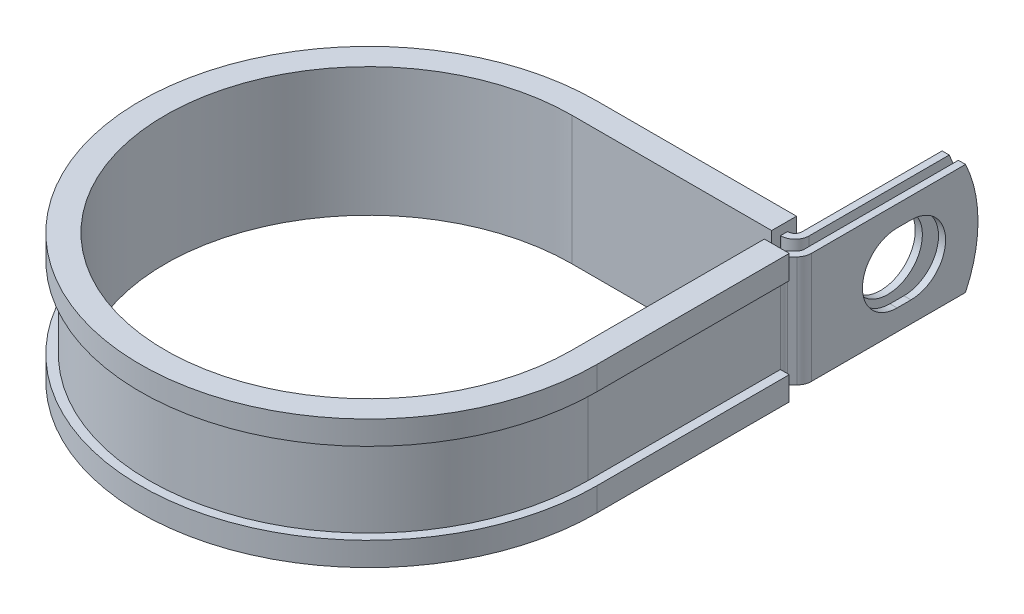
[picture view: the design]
ISO-10303-21;
HEADER;
FILE_DESCRIPTION(('STEP AP214'),'2;1');
FILE_NAME('part.step','',(''),(''),'','','');
FILE_SCHEMA(('AUTOMOTIVE_DESIGN { 1 0 10303 214 1 1 1 1 }'));
ENDSEC;
DATA;
#1=APPLICATION_CONTEXT('core data for automotive mechanical design processes');
#2=APPLICATION_PROTOCOL_DEFINITION('international standard','automotive_design',2000,#1);
#3=PRODUCT_CONTEXT('',#1,'mechanical');
#4=PRODUCT('Part','Part','',(#3));
#5=PRODUCT_RELATED_PRODUCT_CATEGORY('part','',(#4));
#6=PRODUCT_DEFINITION_FORMATION('','',#4);
#7=PRODUCT_DEFINITION_CONTEXT('part definition',#1,'design');
#8=PRODUCT_DEFINITION('design','',#6,#7);
#9=PRODUCT_DEFINITION_SHAPE('','',#8);
#10=(LENGTH_UNIT() NAMED_UNIT(*) SI_UNIT(.MILLI.,.METRE.));
#11=(NAMED_UNIT(*) PLANE_ANGLE_UNIT() SI_UNIT($,.RADIAN.));
#12=(NAMED_UNIT(*) SI_UNIT($,.STERADIAN.) SOLID_ANGLE_UNIT());
#13=UNCERTAINTY_MEASURE_WITH_UNIT(LENGTH_MEASURE(1.E-05),#10,'distance_accuracy_value','');
#14=(GEOMETRIC_REPRESENTATION_CONTEXT(3) GLOBAL_UNCERTAINTY_ASSIGNED_CONTEXT((#13)) GLOBAL_UNIT_ASSIGNED_CONTEXT((#10,
#11,#12)) REPRESENTATION_CONTEXT('',''));
#15=CARTESIAN_POINT('',(0.,0.,0.));
#16=DIRECTION('',(0.,0.,1.));
#17=DIRECTION('',(1.,0.,0.));
#18=AXIS2_PLACEMENT_3D('',#15,#16,#17);
#19=CARTESIAN_POINT('',(37.1272698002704,-9.525,-36.449));
#20=DIRECTION('',(0.,1.,0.));
#21=DIRECTION('',(1.,0.,0.));
#22=AXIS2_PLACEMENT_3D('',#19,#20,#21);
#23=PLANE('',#22);
#24=DIRECTION('',(0.,0.,-1.));
#25=VECTOR('',#24,1.);
#26=CARTESIAN_POINT('',(34.2824698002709,-9.525,-36.449));
#27=LINE('',#26,#25);
#28=CARTESIAN_POINT('',(34.2824698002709,-9.525,-36.449));
#29=VERTEX_POINT('',#28);
#30=CARTESIAN_POINT('',(34.282469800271,-9.525,-37.6682));
#31=VERTEX_POINT('',#30);
#32=EDGE_CURVE('E505',#29,#31,#27,.T.);
#33=ORIENTED_EDGE('',*,*,#32,.T.);
#34=DIRECTION('',(1.,0.,0.));
#35=VECTOR('',#34,1.);
#36=CARTESIAN_POINT('',(0.,-9.525,-37.6682));
#37=LINE('',#36,#35);
#38=CARTESIAN_POINT('',(34.3332698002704,-9.525,-37.6682));
#39=VERTEX_POINT('',#38);
#40=EDGE_CURVE('E392',#39,#31,#37,.F.);
#41=ORIENTED_EDGE('',*,*,#40,.F.);
#42=CARTESIAN_POINT('',(34.3332698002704,-9.525,-38.8874));
#43=DIRECTION('',(0.,1.,0.));
#44=DIRECTION('',(1.,0.,0.));
#45=AXIS2_PLACEMENT_3D('',#42,#43,#44);
#46=CIRCLE('',#45,1.2192);
#47=CARTESIAN_POINT('',(35.5524698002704,-9.525,-38.8874));
#48=VERTEX_POINT('',#47);
#49=EDGE_CURVE('E390',#48,#39,#46,.F.);
#50=ORIENTED_EDGE('',*,*,#49,.F.);
#51=DIRECTION('',(0.,0.,1.));
#52=VECTOR('',#51,1.);
#53=CARTESIAN_POINT('',(35.5524698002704,-9.525,-65.0748));
#54=LINE('',#53,#52);
#55=CARTESIAN_POINT('',(35.5524698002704,-9.525,-62.9302631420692));
#56=VERTEX_POINT('',#55);
#57=EDGE_CURVE('E388',#56,#48,#54,.T.);
#58=ORIENTED_EDGE('',*,*,#57,.F.);
#59=DIRECTION('',(-1.,0.,0.));
#60=VECTOR('',#59,1.);
#61=CARTESIAN_POINT('',(39.5656698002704,-9.525,-62.9302631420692));
#62=LINE('',#61,#60);
#63=CARTESIAN_POINT('',(36.7716698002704,-9.525,-62.9302631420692));
#64=VERTEX_POINT('',#63);
#65=EDGE_CURVE('E11',#64,#56,#62,.T.);
#66=ORIENTED_EDGE('',*,*,#65,.F.);
#67=DIRECTION('',(0.,0.,1.));
#68=VECTOR('',#67,1.);
#69=CARTESIAN_POINT('',(36.7716698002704,-9.525,-65.0748));
#70=LINE('',#69,#68);
#71=CARTESIAN_POINT('',(36.7716698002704,-9.525,-38.8874));
#72=VERTEX_POINT('',#71);
#73=EDGE_CURVE('E386',#64,#72,#70,.T.);
#74=ORIENTED_EDGE('',*,*,#73,.T.);
#75=CARTESIAN_POINT('',(34.3332698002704,-9.525,-38.8874));
#76=DIRECTION('',(0.,-1.,0.));
#77=DIRECTION('',(0.,0.,1.));
#78=AXIS2_PLACEMENT_3D('',#75,#76,#77);
#79=CIRCLE('',#78,2.4384);
#80=CARTESIAN_POINT('',(34.3332698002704,-9.525,-36.449));
#81=VERTEX_POINT('',#80);
#82=EDGE_CURVE('E383',#72,#81,#79,.T.);
#83=ORIENTED_EDGE('',*,*,#82,.T.);
#84=DIRECTION('',(-1.,0.,0.));
#85=VECTOR('',#84,1.);
#86=CARTESIAN_POINT('',(0.,-9.525,-36.449));
#87=LINE('',#86,#85);
#88=EDGE_CURVE('E380',#81,#29,#87,.T.);
#89=ORIENTED_EDGE('',*,*,#88,.T.);
#90=EDGE_LOOP('',(#33,#41,#50,#58,#66,#74,#83,#89));
#91=FACE_BOUND('',#90,.T.);
#92=ADVANCED_FACE('F36',(#91),#23,.F.);
#93=CARTESIAN_POINT('',(37.1272698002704,9.525,-36.449));
#94=DIRECTION('',(0.,1.,0.));
#95=DIRECTION('',(1.,0.,0.));
#96=AXIS2_PLACEMENT_3D('',#93,#94,#95);
#97=PLANE('',#96);
#98=DIRECTION('',(1.,0.,0.));
#99=VECTOR('',#98,1.);
#100=CARTESIAN_POINT('',(0.,9.525,-37.6682));
#101=LINE('',#100,#99);
#102=CARTESIAN_POINT('',(34.3332698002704,9.525,-37.6682));
#103=VERTEX_POINT('',#102);
#104=CARTESIAN_POINT('',(34.282469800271,9.525,-37.6682));
#105=VERTEX_POINT('',#104);
#106=EDGE_CURVE('E350',#103,#105,#101,.F.);
#107=ORIENTED_EDGE('',*,*,#106,.T.);
#108=DIRECTION('',(0.,0.,1.));
#109=VECTOR('',#108,1.);
#110=CARTESIAN_POINT('',(34.282469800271,9.525,-37.6682));
#111=LINE('',#110,#109);
#112=CARTESIAN_POINT('',(34.2824698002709,9.525,-36.449));
#113=VERTEX_POINT('',#112);
#114=EDGE_CURVE('E499',#105,#113,#111,.T.);
#115=ORIENTED_EDGE('',*,*,#114,.T.);
#116=DIRECTION('',(-1.,0.,0.));
#117=VECTOR('',#116,1.);
#118=CARTESIAN_POINT('',(0.,9.525,-36.449));
#119=LINE('',#118,#117);
#120=CARTESIAN_POINT('',(34.3332698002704,9.525,-36.449));
#121=VERTEX_POINT('',#120);
#122=EDGE_CURVE('E607',#121,#113,#119,.T.);
#123=ORIENTED_EDGE('',*,*,#122,.F.);
#124=CARTESIAN_POINT('',(34.3332698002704,9.525,-38.8874));
#125=DIRECTION('',(0.,-1.,0.));
#126=DIRECTION('',(0.,0.,1.));
#127=AXIS2_PLACEMENT_3D('',#124,#125,#126);
#128=CIRCLE('',#127,2.4384);
#129=CARTESIAN_POINT('',(36.7716698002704,9.525,-38.8874));
#130=VERTEX_POINT('',#129);
#131=EDGE_CURVE('E352',#130,#121,#128,.T.);
#132=ORIENTED_EDGE('',*,*,#131,.F.);
#133=DIRECTION('',(0.,0.,1.));
#134=VECTOR('',#133,1.);
#135=CARTESIAN_POINT('',(36.7716698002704,9.525,-65.0748));
#136=LINE('',#135,#134);
#137=CARTESIAN_POINT('',(36.7716698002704,9.525,-62.9302631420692));
#138=VERTEX_POINT('',#137);
#139=EDGE_CURVE('E343',#138,#130,#136,.T.);
#140=ORIENTED_EDGE('',*,*,#139,.F.);
#141=DIRECTION('',(-1.,0.,0.));
#142=VECTOR('',#141,1.);
#143=CARTESIAN_POINT('',(39.5656698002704,9.525,-62.9302631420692));
#144=LINE('',#143,#142);
#145=CARTESIAN_POINT('',(35.5524698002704,9.525,-62.9302631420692));
#146=VERTEX_POINT('',#145);
#147=EDGE_CURVE('E44',#138,#146,#144,.T.);
#148=ORIENTED_EDGE('',*,*,#147,.T.);
#149=DIRECTION('',(0.,0.,1.));
#150=VECTOR('',#149,1.);
#151=CARTESIAN_POINT('',(35.5524698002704,9.525,-65.0748));
#152=LINE('',#151,#150);
#153=CARTESIAN_POINT('',(35.5524698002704,9.525,-38.8874));
#154=VERTEX_POINT('',#153);
#155=EDGE_CURVE('E340',#146,#154,#152,.T.);
#156=ORIENTED_EDGE('',*,*,#155,.T.);
#157=CARTESIAN_POINT('',(34.3332698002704,9.525,-38.8874));
#158=DIRECTION('',(0.,1.,0.));
#159=DIRECTION('',(1.,0.,0.));
#160=AXIS2_PLACEMENT_3D('',#157,#158,#159);
#161=CIRCLE('',#160,1.2192);
#162=EDGE_CURVE('E348',#154,#103,#161,.F.);
#163=ORIENTED_EDGE('',*,*,#162,.T.);
#164=EDGE_LOOP('',(#107,#115,#123,#132,#140,#148,#156,#163));
#165=FACE_BOUND('',#164,.T.);
#166=ADVANCED_FACE('F339',(#165),#97,.T.);
#167=CARTESIAN_POINT('',(0.,9.525,-36.449));
#168=DIRECTION('',(0.,0.,1.));
#169=DIRECTION('',(1.,0.,0.));
#170=AXIS2_PLACEMENT_3D('',#167,#168,#169);
#171=PLANE('',#170);
#172=ORIENTED_EDGE('',*,*,#122,.T.);
#173=DIRECTION('',(0.,-1.,0.));
#174=VECTOR('',#173,1.);
#175=CARTESIAN_POINT('',(34.2824698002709,9.525,-36.449));
#176=LINE('',#175,#174);
#177=EDGE_CURVE('E502',#113,#29,#176,.T.);
#178=ORIENTED_EDGE('',*,*,#177,.T.);
#179=ORIENTED_EDGE('',*,*,#88,.F.);
#180=DIRECTION('',(0.,-1.,0.));
#181=VECTOR('',#180,1.);
#182=CARTESIAN_POINT('',(34.3332698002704,9.525,-36.449));
#183=LINE('',#182,#181);
#184=EDGE_CURVE('E326',#121,#81,#183,.T.);
#185=ORIENTED_EDGE('',*,*,#184,.F.);
#186=EDGE_LOOP('',(#172,#178,#179,#185));
#187=FACE_BOUND('',#186,.T.);
#188=ADVANCED_FACE('F617',(#187),#171,.T.);
#189=CARTESIAN_POINT('',(39.5656698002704,9.525,-36.449));
#190=DIRECTION('',(-1.,0.,0.));
#191=DIRECTION('',(0.,0.,1.));
#192=AXIS2_PLACEMENT_3D('',#189,#190,#191);
#193=PLANE('',#192);
#194=CARTESIAN_POINT('',(39.5656698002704,0.,-53.5685999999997));
#195=DIRECTION('',(1.,0.,0.));
#196=DIRECTION('',(0.,0.,-1.));
#197=AXIS2_PLACEMENT_3D('',#194,#195,#196);
#198=CIRCLE('',#197,5.9436);
#199=CARTESIAN_POINT('',(39.5656698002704,-5.9436,-53.5686000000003));
#200=VERTEX_POINT('',#199);
#201=CARTESIAN_POINT('',(39.5656698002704,5.9436,-53.5686000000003));
#202=VERTEX_POINT('',#201);
#203=EDGE_CURVE('E562',#200,#202,#198,.T.);
#204=ORIENTED_EDGE('',*,*,#203,.F.);
#205=DIRECTION('',(0.,0.,-1.));
#206=VECTOR('',#205,1.);
#207=CARTESIAN_POINT('',(39.5656698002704,-5.9436,-51.1809999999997));
#208=LINE('',#207,#206);
#209=CARTESIAN_POINT('',(39.5656698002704,-5.9436,-51.1809999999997));
#210=VERTEX_POINT('',#209);
#211=EDGE_CURVE('E565',#210,#200,#208,.T.);
#212=ORIENTED_EDGE('',*,*,#211,.F.);
#213=CARTESIAN_POINT('',(39.5656698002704,0.,-51.1809999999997));
#214=DIRECTION('',(1.,0.,0.));
#215=DIRECTION('',(0.,0.,-1.));
#216=AXIS2_PLACEMENT_3D('',#213,#214,#215);
#217=CIRCLE('',#216,5.9436);
#218=CARTESIAN_POINT('',(39.5656698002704,5.9436,-51.1809999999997));
#219=VERTEX_POINT('',#218);
#220=EDGE_CURVE('E558',#219,#210,#217,.T.);
#221=ORIENTED_EDGE('',*,*,#220,.F.);
#222=DIRECTION('',(0.,0.,1.));
#223=VECTOR('',#222,1.);
#224=CARTESIAN_POINT('',(39.5656698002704,5.9436,-51.1809999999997));
#225=LINE('',#224,#223);
#226=EDGE_CURVE('E559',#202,#219,#225,.T.);
#227=ORIENTED_EDGE('',*,*,#226,.F.);
#228=EDGE_LOOP('',(#204,#212,#221,#227));
#229=FACE_BOUND('',#228,.T.);
#230=DIRECTION('',(0.,0.,-1.));
#231=VECTOR('',#230,1.);
#232=CARTESIAN_POINT('',(39.5656698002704,-9.525,-36.449));
#233=LINE('',#232,#231);
#234=CARTESIAN_POINT('',(39.5656698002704,-9.525,-36.449));
#235=VERTEX_POINT('',#234);
#236=CARTESIAN_POINT('',(39.5656698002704,-9.525,-62.9302631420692));
#237=VERTEX_POINT('',#236);
#238=EDGE_CURVE('E364',#235,#237,#233,.T.);
#239=ORIENTED_EDGE('',*,*,#238,.T.);
#240=CARTESIAN_POINT('',(39.5656698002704,0.,-42.8498));
#241=DIRECTION('',(-1.,0.,0.));
#242=DIRECTION('',(0.,0.,1.));
#243=AXIS2_PLACEMENT_3D('',#240,#241,#242);
#244=CIRCLE('',#243,22.225);
#245=CARTESIAN_POINT('',(39.5656698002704,9.525,-62.9302631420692));
#246=VERTEX_POINT('',#245);
#247=EDGE_CURVE('E550',#246,#237,#244,.T.);
#248=ORIENTED_EDGE('',*,*,#247,.F.);
#249=DIRECTION('',(0.,0.,-1.));
#250=VECTOR('',#249,1.);
#251=CARTESIAN_POINT('',(39.5656698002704,9.525,-36.449));
#252=LINE('',#251,#250);
#253=CARTESIAN_POINT('',(39.5656698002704,9.525,-36.449));
#254=VERTEX_POINT('',#253);
#255=EDGE_CURVE('E401',#254,#246,#252,.T.);
#256=ORIENTED_EDGE('',*,*,#255,.F.);
#257=DIRECTION('',(0.,-1.,0.));
#258=VECTOR('',#257,1.);
#259=CARTESIAN_POINT('',(39.5656698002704,9.525,-36.449));
#260=LINE('',#259,#258);
#261=EDGE_CURVE('E363',#254,#235,#260,.T.);
#262=ORIENTED_EDGE('',*,*,#261,.T.);
#263=EDGE_LOOP('',(#239,#248,#256,#262));
#264=FACE_BOUND('',#263,.T.);
#265=ADVANCED_FACE('F38',(#229,#264),#193,.F.);
#266=CARTESIAN_POINT('',(38.3464698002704,9.525,-36.449));
#267=DIRECTION('',(-1.,0.,0.));
#268=DIRECTION('',(0.,0.,1.));
#269=AXIS2_PLACEMENT_3D('',#266,#267,#268);
#270=PLANE('',#269);
#271=DIRECTION('',(0.,0.,-1.));
#272=VECTOR('',#271,1.);
#273=CARTESIAN_POINT('',(38.3464698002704,-5.9436,-51.1809999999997));
#274=LINE('',#273,#272);
#275=CARTESIAN_POINT('',(38.3464698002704,-5.9436,-51.1809999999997));
#276=VERTEX_POINT('',#275);
#277=CARTESIAN_POINT('',(38.3464698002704,-5.9436,-53.5686000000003));
#278=VERTEX_POINT('',#277);
#279=EDGE_CURVE('E561',#276,#278,#274,.T.);
#280=ORIENTED_EDGE('',*,*,#279,.T.);
#281=CARTESIAN_POINT('',(38.3464698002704,0.,-53.5685999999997));
#282=DIRECTION('',(-1.,0.,0.));
#283=DIRECTION('',(0.,0.,1.));
#284=AXIS2_PLACEMENT_3D('',#281,#282,#283);
#285=CIRCLE('',#284,5.9436);
#286=CARTESIAN_POINT('',(38.3464698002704,5.9436,-53.5686000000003));
#287=VERTEX_POINT('',#286);
#288=EDGE_CURVE('E582',#278,#287,#285,.F.);
#289=ORIENTED_EDGE('',*,*,#288,.T.);
#290=DIRECTION('',(0.,0.,1.));
#291=VECTOR('',#290,1.);
#292=CARTESIAN_POINT('',(38.3464698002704,5.9436,-51.1809999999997));
#293=LINE('',#292,#291);
#294=CARTESIAN_POINT('',(38.3464698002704,5.9436,-51.1809999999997));
#295=VERTEX_POINT('',#294);
#296=EDGE_CURVE('E578',#287,#295,#293,.T.);
#297=ORIENTED_EDGE('',*,*,#296,.T.);
#298=CARTESIAN_POINT('',(38.3464698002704,0.,-51.1809999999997));
#299=DIRECTION('',(-1.,0.,0.));
#300=DIRECTION('',(0.,0.,1.));
#301=AXIS2_PLACEMENT_3D('',#298,#299,#300);
#302=CIRCLE('',#301,5.9436);
#303=EDGE_CURVE('E573',#295,#276,#302,.F.);
#304=ORIENTED_EDGE('',*,*,#303,.T.);
#305=EDGE_LOOP('',(#280,#289,#297,#304));
#306=FACE_BOUND('',#305,.T.);
#307=CARTESIAN_POINT('',(38.3464698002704,0.,-42.8498));
#308=DIRECTION('',(-1.,0.,0.));
#309=DIRECTION('',(0.,0.,1.));
#310=AXIS2_PLACEMENT_3D('',#307,#308,#309);
#311=CIRCLE('',#310,22.225);
#312=CARTESIAN_POINT('',(38.3464698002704,9.525,-62.9302631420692));
#313=VERTEX_POINT('',#312);
#314=CARTESIAN_POINT('',(38.3464698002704,-9.525,-62.9302631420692));
#315=VERTEX_POINT('',#314);
#316=EDGE_CURVE('E58',#313,#315,#311,.T.);
#317=ORIENTED_EDGE('',*,*,#316,.T.);
#318=DIRECTION('',(0.,0.,-1.));
#319=VECTOR('',#318,1.);
#320=CARTESIAN_POINT('',(38.3464698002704,-9.525,-36.449));
#321=LINE('',#320,#319);
#322=CARTESIAN_POINT('',(38.3464698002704,-9.525,-36.449));
#323=VERTEX_POINT('',#322);
#324=EDGE_CURVE('E367',#323,#315,#321,.T.);
#325=ORIENTED_EDGE('',*,*,#324,.F.);
#326=DIRECTION('',(0.,-1.,0.));
#327=VECTOR('',#326,1.);
#328=CARTESIAN_POINT('',(38.3464698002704,9.525,-36.449));
#329=LINE('',#328,#327);
#330=CARTESIAN_POINT('',(38.3464698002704,9.525,-36.449));
#331=VERTEX_POINT('',#330);
#332=EDGE_CURVE('E334',#331,#323,#329,.T.);
#333=ORIENTED_EDGE('',*,*,#332,.F.);
#334=DIRECTION('',(0.,0.,-1.));
#335=VECTOR('',#334,1.);
#336=CARTESIAN_POINT('',(38.3464698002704,9.525,-36.449));
#337=LINE('',#336,#335);
#338=EDGE_CURVE('E597',#331,#313,#337,.T.);
#339=ORIENTED_EDGE('',*,*,#338,.T.);
#340=EDGE_LOOP('',(#317,#325,#333,#339));
#341=FACE_BOUND('',#340,.T.);
#342=ADVANCED_FACE('F671',(#306,#341),#270,.T.);
#343=CARTESIAN_POINT('',(36.7716698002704,9.525,-65.0748));
#344=DIRECTION('',(1.,0.,0.));
#345=DIRECTION('',(0.,0.,-1.));
#346=AXIS2_PLACEMENT_3D('',#343,#344,#345);
#347=PLANE('',#346);
#348=CARTESIAN_POINT('',(36.7716698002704,0.,-52.3748));
#349=DIRECTION('',(1.,0.,0.));
#350=DIRECTION('',(0.,0.,-1.));
#351=AXIS2_PLACEMENT_3D('',#348,#349,#350);
#352=CIRCLE('',#351,5.9436);
#353=CARTESIAN_POINT('',(36.7716698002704,0.,-58.3184));
#354=VERTEX_POINT('',#353);
#355=EDGE_CURVE('E368',#354,#354,#352,.F.);
#356=ORIENTED_EDGE('',*,*,#355,.T.);
#357=EDGE_LOOP('',(#356));
#358=FACE_BOUND('',#357,.T.);
#359=ORIENTED_EDGE('',*,*,#73,.F.);
#360=CARTESIAN_POINT('',(36.7716698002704,0.,-42.8498));
#361=DIRECTION('',(1.,0.,0.));
#362=DIRECTION('',(0.,0.,-1.));
#363=AXIS2_PLACEMENT_3D('',#360,#361,#362);
#364=CIRCLE('',#363,22.225);
#365=EDGE_CURVE('E555',#64,#138,#364,.T.);
#366=ORIENTED_EDGE('',*,*,#365,.T.);
#367=ORIENTED_EDGE('',*,*,#139,.T.);
#368=DIRECTION('',(0.,-1.,0.));
#369=VECTOR('',#368,1.);
#370=CARTESIAN_POINT('',(36.7716698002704,9.525,-38.8874));
#371=LINE('',#370,#369);
#372=EDGE_CURVE('E323',#130,#72,#371,.T.);
#373=ORIENTED_EDGE('',*,*,#372,.T.);
#374=EDGE_LOOP('',(#359,#366,#367,#373));
#375=FACE_BOUND('',#374,.T.);
#376=ADVANCED_FACE('F623',(#358,#375),#347,.T.);
#377=CARTESIAN_POINT('',(35.5524698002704,9.525,-65.0748));
#378=DIRECTION('',(1.,0.,0.));
#379=DIRECTION('',(0.,0.,-1.));
#380=AXIS2_PLACEMENT_3D('',#377,#378,#379);
#381=PLANE('',#380);
#382=CARTESIAN_POINT('',(35.5524698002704,0.,-52.3748));
#383=DIRECTION('',(-1.,0.,0.));
#384=DIRECTION('',(0.,0.,1.));
#385=AXIS2_PLACEMENT_3D('',#382,#383,#384);
#386=CIRCLE('',#385,5.9436);
#387=CARTESIAN_POINT('',(35.5524698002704,0.,-46.4312));
#388=VERTEX_POINT('',#387);
#389=EDGE_CURVE('E590',#388,#388,#386,.T.);
#390=ORIENTED_EDGE('',*,*,#389,.F.);
#391=EDGE_LOOP('',(#390));
#392=FACE_BOUND('',#391,.T.);
#393=CARTESIAN_POINT('',(35.5524698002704,0.,-42.8498));
#394=DIRECTION('',(-1.,0.,0.));
#395=DIRECTION('',(0.,0.,1.));
#396=AXIS2_PLACEMENT_3D('',#393,#394,#395);
#397=CIRCLE('',#396,22.225);
#398=EDGE_CURVE('E50',#146,#56,#397,.T.);
#399=ORIENTED_EDGE('',*,*,#398,.T.);
#400=ORIENTED_EDGE('',*,*,#57,.T.);
#401=DIRECTION('',(0.,-1.,0.));
#402=VECTOR('',#401,1.);
#403=CARTESIAN_POINT('',(35.5524698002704,9.525,-38.8874));
#404=LINE('',#403,#402);
#405=EDGE_CURVE('E320',#154,#48,#404,.T.);
#406=ORIENTED_EDGE('',*,*,#405,.F.);
#407=ORIENTED_EDGE('',*,*,#155,.F.);
#408=EDGE_LOOP('',(#399,#400,#406,#407));
#409=FACE_BOUND('',#408,.T.);
#410=ADVANCED_FACE('F346',(#392,#409),#381,.F.);
#411=CARTESIAN_POINT('',(38.8874,-9.525,-33.0365026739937));
#412=DIRECTION('',(0.,1.,0.));
#413=DIRECTION('',(1.,0.,0.));
#414=AXIS2_PLACEMENT_3D('',#411,#412,#413);
#415=CIRCLE('',#414,1.2192);
#416=CARTESIAN_POINT('',(37.6682,-9.525,-33.0365026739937));
#417=VERTEX_POINT('',#416);
#418=CARTESIAN_POINT('',(38.0252954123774,-9.525,-33.8986072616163));
#419=VERTEX_POINT('',#418);
#420=EDGE_CURVE('E395',#417,#419,#415,.F.);
#421=ORIENTED_EDGE('',*,*,#420,.F.);
#422=DIRECTION('',(1.,0.,0.));
#423=VECTOR('',#422,1.);
#424=CARTESIAN_POINT('',(36.449,-9.525,-33.0365026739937));
#425=LINE('',#424,#423);
#426=CARTESIAN_POINT('',(36.449,-9.525,-33.0365026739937));
#427=VERTEX_POINT('',#426);
#428=EDGE_CURVE('E433',#427,#417,#425,.T.);
#429=ORIENTED_EDGE('',*,*,#428,.F.);
#430=CARTESIAN_POINT('',(38.8874,-9.525,-33.0365026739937));
#431=DIRECTION('',(0.,-1.,0.));
#432=DIRECTION('',(0.,0.,1.));
#433=AXIS2_PLACEMENT_3D('',#430,#431,#432);
#434=CIRCLE('',#433,2.4384);
#435=CARTESIAN_POINT('',(37.1631908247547,-9.525,-34.760711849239));
#436=VERTEX_POINT('',#435);
#437=EDGE_CURVE('E377',#427,#436,#434,.T.);
#438=ORIENTED_EDGE('',*,*,#437,.T.);
#439=DIRECTION('',(0.707106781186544,0.,-0.70710678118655));
#440=VECTOR('',#439,1.);
#441=CARTESIAN_POINT('',(37.1631908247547,-9.525,-34.760711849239));
#442=LINE('',#441,#440);
#443=CARTESIAN_POINT('',(37.9893743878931,-9.525,-35.5868954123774));
#444=VERTEX_POINT('',#443);
#445=EDGE_CURVE('E374',#436,#444,#442,.T.);
#446=ORIENTED_EDGE('',*,*,#445,.T.);
#447=CARTESIAN_POINT('',(37.1272698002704,-9.525,-36.449));
#448=DIRECTION('',(0.,1.,0.));
#449=DIRECTION('',(0.,0.,1.));
#450=AXIS2_PLACEMENT_3D('',#447,#448,#449);
#451=CIRCLE('',#450,1.2192);
#452=EDGE_CURVE('E371',#444,#323,#451,.T.);
#453=ORIENTED_EDGE('',*,*,#452,.T.);
#454=ORIENTED_EDGE('',*,*,#324,.T.);
#455=DIRECTION('',(-1.,0.,0.));
#456=VECTOR('',#455,1.);
#457=CARTESIAN_POINT('',(39.5656698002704,-9.525,-62.9302631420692));
#458=LINE('',#457,#456);
#459=EDGE_CURVE('E548',#237,#315,#458,.T.);
#460=ORIENTED_EDGE('',*,*,#459,.F.);
#461=ORIENTED_EDGE('',*,*,#238,.F.);
#462=CARTESIAN_POINT('',(37.1272698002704,-9.525,-36.449));
#463=DIRECTION('',(0.,1.,0.));
#464=DIRECTION('',(1.,0.,0.));
#465=AXIS2_PLACEMENT_3D('',#462,#463,#464);
#466=CIRCLE('',#465,2.4384);
#467=CARTESIAN_POINT('',(38.8514789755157,-9.525,-34.7247908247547));
#468=VERTEX_POINT('',#467);
#469=EDGE_CURVE('E399',#468,#235,#466,.T.);
#470=ORIENTED_EDGE('',*,*,#469,.F.);
#471=DIRECTION('',(0.707106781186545,0.,-0.707106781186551));
#472=VECTOR('',#471,1.);
#473=CARTESIAN_POINT('',(38.0252954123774,-9.525,-33.8986072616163));
#474=LINE('',#473,#472);
#475=EDGE_CURVE('E397',#419,#468,#474,.T.);
#476=ORIENTED_EDGE('',*,*,#475,.F.);
#477=EDGE_LOOP('',(#421,#429,#438,#446,#453,#454,#460,#461,#470,#476));
#478=FACE_BOUND('',#477,.T.);
#479=ADVANCED_FACE('F657',(#478),#23,.F.);
#480=DIRECTION('',(-1.,0.,0.));
#481=VECTOR('',#480,1.);
#482=CARTESIAN_POINT('',(37.6682,9.525,-33.0365026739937));
#483=LINE('',#482,#481);
#484=CARTESIAN_POINT('',(37.6682,9.525,-33.0365026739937));
#485=VERTEX_POINT('',#484);
#486=CARTESIAN_POINT('',(36.449,9.525,-33.0365026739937));
#487=VERTEX_POINT('',#486);
#488=EDGE_CURVE('E422',#485,#487,#483,.T.);
#489=ORIENTED_EDGE('',*,*,#488,.F.);
#490=CARTESIAN_POINT('',(38.8874,9.525,-33.0365026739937));
#491=DIRECTION('',(0.,1.,0.));
#492=DIRECTION('',(1.,0.,0.));
#493=AXIS2_PLACEMENT_3D('',#490,#491,#492);
#494=CIRCLE('',#493,1.2192);
#495=CARTESIAN_POINT('',(38.0252954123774,9.525,-33.8986072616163));
#496=VERTEX_POINT('',#495);
#497=EDGE_CURVE('E357',#485,#496,#494,.F.);
#498=ORIENTED_EDGE('',*,*,#497,.T.);
#499=DIRECTION('',(0.707106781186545,0.,-0.707106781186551));
#500=VECTOR('',#499,1.);
#501=CARTESIAN_POINT('',(38.0252954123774,9.525,-33.8986072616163));
#502=LINE('',#501,#500);
#503=CARTESIAN_POINT('',(38.8514789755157,9.525,-34.7247908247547));
#504=VERTEX_POINT('',#503);
#505=EDGE_CURVE('E359',#496,#504,#502,.T.);
#506=ORIENTED_EDGE('',*,*,#505,.T.);
#507=CARTESIAN_POINT('',(37.1272698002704,9.525,-36.449));
#508=DIRECTION('',(0.,1.,0.));
#509=DIRECTION('',(1.,0.,0.));
#510=AXIS2_PLACEMENT_3D('',#507,#508,#509);
#511=CIRCLE('',#510,2.4384);
#512=EDGE_CURVE('E361',#504,#254,#511,.T.);
#513=ORIENTED_EDGE('',*,*,#512,.T.);
#514=ORIENTED_EDGE('',*,*,#255,.T.);
#515=DIRECTION('',(-1.,0.,0.));
#516=VECTOR('',#515,1.);
#517=CARTESIAN_POINT('',(39.5656698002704,9.525,-62.9302631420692));
#518=LINE('',#517,#516);
#519=EDGE_CURVE('E552',#246,#313,#518,.T.);
#520=ORIENTED_EDGE('',*,*,#519,.T.);
#521=ORIENTED_EDGE('',*,*,#338,.F.);
#522=CARTESIAN_POINT('',(37.1272698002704,9.525,-36.449));
#523=DIRECTION('',(0.,1.,0.));
#524=DIRECTION('',(0.,0.,1.));
#525=AXIS2_PLACEMENT_3D('',#522,#523,#524);
#526=CIRCLE('',#525,1.2192);
#527=CARTESIAN_POINT('',(37.9893743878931,9.525,-35.5868954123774));
#528=VERTEX_POINT('',#527);
#529=EDGE_CURVE('E600',#528,#331,#526,.T.);
#530=ORIENTED_EDGE('',*,*,#529,.F.);
#531=DIRECTION('',(0.707106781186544,0.,-0.70710678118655));
#532=VECTOR('',#531,1.);
#533=CARTESIAN_POINT('',(37.1631908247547,9.525,-34.760711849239));
#534=LINE('',#533,#532);
#535=CARTESIAN_POINT('',(37.1631908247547,9.525,-34.760711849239));
#536=VERTEX_POINT('',#535);
#537=EDGE_CURVE('E603',#536,#528,#534,.T.);
#538=ORIENTED_EDGE('',*,*,#537,.F.);
#539=CARTESIAN_POINT('',(38.8874,9.525,-33.0365026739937));
#540=DIRECTION('',(0.,-1.,0.));
#541=DIRECTION('',(0.,0.,1.));
#542=AXIS2_PLACEMENT_3D('',#539,#540,#541);
#543=CIRCLE('',#542,2.4384);
#544=EDGE_CURVE('E432',#487,#536,#543,.T.);
#545=ORIENTED_EDGE('',*,*,#544,.F.);
#546=EDGE_LOOP('',(#489,#498,#506,#513,#514,#520,#521,#530,#538,#545));
#547=FACE_BOUND('',#546,.T.);
#548=ADVANCED_FACE('F429',(#547),#97,.T.);
#549=CARTESIAN_POINT('',(37.1272698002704,9.525,-36.449));
#550=DIRECTION('',(0.,-1.,0.));
#551=DIRECTION('',(0.,0.,-1.));
#552=AXIS2_PLACEMENT_3D('',#549,#550,#551);
#553=CYLINDRICAL_SURFACE('',#552,1.2192);
#554=ORIENTED_EDGE('',*,*,#452,.F.);
#555=DIRECTION('',(0.,-1.,0.));
#556=VECTOR('',#555,1.);
#557=CARTESIAN_POINT('',(37.9893743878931,9.525,-35.5868954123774));
#558=LINE('',#557,#556);
#559=EDGE_CURVE('E332',#528,#444,#558,.T.);
#560=ORIENTED_EDGE('',*,*,#559,.F.);
#561=ORIENTED_EDGE('',*,*,#529,.T.);
#562=ORIENTED_EDGE('',*,*,#332,.T.);
#563=EDGE_LOOP('',(#554,#560,#561,#562));
#564=FACE_BOUND('',#563,.T.);
#565=ADVANCED_FACE('F667',(#564),#553,.F.);
#566=CARTESIAN_POINT('',(37.1631908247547,9.525,-34.760711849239));
#567=DIRECTION('',(-0.70710678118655,0.,-0.707106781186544));
#568=DIRECTION('',(-0.707106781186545,0.,0.707106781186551));
#569=AXIS2_PLACEMENT_3D('',#566,#567,#568);
#570=PLANE('',#569);
#571=ORIENTED_EDGE('',*,*,#445,.F.);
#572=DIRECTION('',(0.,-1.,0.));
#573=VECTOR('',#572,1.);
#574=CARTESIAN_POINT('',(37.1631908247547,9.525,-34.760711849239));
#575=LINE('',#574,#573);
#576=EDGE_CURVE('E330',#536,#436,#575,.T.);
#577=ORIENTED_EDGE('',*,*,#576,.F.);
#578=ORIENTED_EDGE('',*,*,#537,.T.);
#579=ORIENTED_EDGE('',*,*,#559,.T.);
#580=EDGE_LOOP('',(#571,#577,#578,#579));
#581=FACE_BOUND('',#580,.T.);
#582=ADVANCED_FACE('F662',(#581),#570,.T.);
#583=CARTESIAN_POINT('',(38.8874,9.525,-33.0365026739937));
#584=DIRECTION('',(0.,-1.,0.));
#585=DIRECTION('',(0.,0.,-1.));
#586=AXIS2_PLACEMENT_3D('',#583,#584,#585);
#587=CYLINDRICAL_SURFACE('',#586,2.4384);
#588=ORIENTED_EDGE('',*,*,#437,.F.);
#589=DIRECTION('',(0.,-1.,0.));
#590=VECTOR('',#589,1.);
#591=CARTESIAN_POINT('',(36.449,9.525,-33.0365026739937));
#592=LINE('',#591,#590);
#593=EDGE_CURVE('E328',#487,#427,#592,.T.);
#594=ORIENTED_EDGE('',*,*,#593,.F.);
#595=ORIENTED_EDGE('',*,*,#544,.T.);
#596=ORIENTED_EDGE('',*,*,#576,.T.);
#597=EDGE_LOOP('',(#588,#594,#595,#596));
#598=FACE_BOUND('',#597,.T.);
#599=ADVANCED_FACE('F659',(#598),#587,.T.);
#600=CARTESIAN_POINT('',(34.3332698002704,9.525,-38.8874));
#601=DIRECTION('',(0.,-1.,0.));
#602=DIRECTION('',(0.,0.,-1.));
#603=AXIS2_PLACEMENT_3D('',#600,#601,#602);
#604=CYLINDRICAL_SURFACE('',#603,2.4384);
#605=ORIENTED_EDGE('',*,*,#82,.F.);
#606=ORIENTED_EDGE('',*,*,#372,.F.);
#607=ORIENTED_EDGE('',*,*,#131,.T.);
#608=ORIENTED_EDGE('',*,*,#184,.T.);
#609=EDGE_LOOP('',(#605,#606,#607,#608));
#610=FACE_BOUND('',#609,.T.);
#611=ADVANCED_FACE('F613',(#610),#604,.T.);
#612=CARTESIAN_POINT('',(34.3332698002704,9.525,-38.8874));
#613=DIRECTION('',(0.,-1.,0.));
#614=DIRECTION('',(0.,0.,-1.));
#615=AXIS2_PLACEMENT_3D('',#612,#613,#614);
#616=CYLINDRICAL_SURFACE('',#615,1.2192);
#617=ORIENTED_EDGE('',*,*,#49,.T.);
#618=DIRECTION('',(0.,-1.,0.));
#619=VECTOR('',#618,1.);
#620=CARTESIAN_POINT('',(34.3332698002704,9.525,-37.6682));
#621=LINE('',#620,#619);
#622=EDGE_CURVE('E311',#103,#39,#621,.T.);
#623=ORIENTED_EDGE('',*,*,#622,.F.);
#624=ORIENTED_EDGE('',*,*,#162,.F.);
#625=ORIENTED_EDGE('',*,*,#405,.T.);
#626=EDGE_LOOP('',(#617,#623,#624,#625));
#627=FACE_BOUND('',#626,.T.);
#628=ADVANCED_FACE('F628',(#627),#616,.F.);
#629=CARTESIAN_POINT('',(0.,9.525,-37.6682));
#630=DIRECTION('',(0.,0.,1.));
#631=DIRECTION('',(1.,0.,0.));
#632=AXIS2_PLACEMENT_3D('',#629,#630,#631);
#633=PLANE('',#632);
#634=DIRECTION('',(0.,-1.,0.));
#635=VECTOR('',#634,1.);
#636=CARTESIAN_POINT('',(0.,9.525,-37.6682));
#637=LINE('',#636,#635);
#638=CARTESIAN_POINT('',(5.28377781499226E-13,6.985,-37.6682));
#639=VERTEX_POINT('',#638);
#640=CARTESIAN_POINT('',(5.28377781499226E-13,-6.985,-37.6682));
#641=VERTEX_POINT('',#640);
#642=EDGE_CURVE('E302',#639,#641,#637,.T.);
#643=ORIENTED_EDGE('',*,*,#642,.F.);
#644=DIRECTION('',(1.,0.,0.));
#645=VECTOR('',#644,1.);
#646=CARTESIAN_POINT('',(5.28377781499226E-13,6.985,-37.6682));
#647=LINE('',#646,#645);
#648=CARTESIAN_POINT('',(34.282469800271,6.985,-37.6682));
#649=VERTEX_POINT('',#648);
#650=EDGE_CURVE('E545',#639,#649,#647,.T.);
#651=ORIENTED_EDGE('',*,*,#650,.T.);
#652=DIRECTION('',(0.,1.,0.));
#653=VECTOR('',#652,1.);
#654=CARTESIAN_POINT('',(34.282469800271,9.525,-37.6682));
#655=LINE('',#654,#653);
#656=EDGE_CURVE('E496',#649,#105,#655,.T.);
#657=ORIENTED_EDGE('',*,*,#656,.T.);
#658=ORIENTED_EDGE('',*,*,#106,.F.);
#659=ORIENTED_EDGE('',*,*,#622,.T.);
#660=ORIENTED_EDGE('',*,*,#40,.T.);
#661=DIRECTION('',(0.,1.,0.));
#662=VECTOR('',#661,1.);
#663=CARTESIAN_POINT('',(34.282469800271,-9.525,-37.6682));
#664=LINE('',#663,#662);
#665=CARTESIAN_POINT('',(34.282469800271,-6.985,-37.6682));
#666=VERTEX_POINT('',#665);
#667=EDGE_CURVE('E508',#31,#666,#664,.T.);
#668=ORIENTED_EDGE('',*,*,#667,.T.);
#669=DIRECTION('',(1.,0.,0.));
#670=VECTOR('',#669,1.);
#671=CARTESIAN_POINT('',(5.28377781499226E-13,-6.985,-37.6682));
#672=LINE('',#671,#670);
#673=EDGE_CURVE('E525',#641,#666,#672,.T.);
#674=ORIENTED_EDGE('',*,*,#673,.F.);
#675=EDGE_LOOP('',(#643,#651,#657,#658,#659,#660,#668,#674));
#676=FACE_BOUND('',#675,.T.);
#677=ADVANCED_FACE('F632',(#676),#633,.F.);
#678=CARTESIAN_POINT('',(0.,9.525,0.));
#679=DIRECTION('',(0.,-1.,0.));
#680=DIRECTION('',(0.,0.,-1.));
#681=AXIS2_PLACEMENT_3D('',#678,#679,#680);
#682=CYLINDRICAL_SURFACE('',#681,37.6682);
#683=DIRECTION('',(0.,-1.,0.));
#684=VECTOR('',#683,1.);
#685=CARTESIAN_POINT('',(37.6682,9.525,0.));
#686=LINE('',#685,#684);
#687=CARTESIAN_POINT('',(37.6682,6.985,0.));
#688=VERTEX_POINT('',#687);
#689=CARTESIAN_POINT('',(37.6682,-6.985,0.));
#690=VERTEX_POINT('',#689);
#691=EDGE_CURVE('E300',#688,#690,#686,.T.);
#692=ORIENTED_EDGE('',*,*,#691,.F.);
#693=CARTESIAN_POINT('',(0.,6.985,0.));
#694=DIRECTION('',(0.,-1.,0.));
#695=DIRECTION('',(0.,0.,-1.));
#696=AXIS2_PLACEMENT_3D('',#693,#694,#695);
#697=CIRCLE('',#696,37.6682);
#698=EDGE_CURVE('E494',#688,#639,#697,.T.);
#699=ORIENTED_EDGE('',*,*,#698,.T.);
#700=ORIENTED_EDGE('',*,*,#642,.T.);
#701=CARTESIAN_POINT('',(0.,-6.985,0.));
#702=DIRECTION('',(0.,-1.,0.));
#703=DIRECTION('',(0.,0.,-1.));
#704=AXIS2_PLACEMENT_3D('',#701,#702,#703);
#705=CIRCLE('',#704,37.6682);
#706=EDGE_CURVE('E283',#690,#641,#705,.T.);
#707=ORIENTED_EDGE('',*,*,#706,.F.);
#708=EDGE_LOOP('',(#692,#699,#700,#707));
#709=FACE_BOUND('',#708,.T.);
#710=ADVANCED_FACE('F298',(#709),#682,.T.);
#711=CARTESIAN_POINT('',(37.6682,9.525,0.));
#712=DIRECTION('',(-1.,0.,0.));
#713=DIRECTION('',(0.,0.,1.));
#714=AXIS2_PLACEMENT_3D('',#711,#712,#713);
#715=PLANE('',#714);
#716=DIRECTION('',(0.,-1.,0.));
#717=VECTOR('',#716,1.);
#718=CARTESIAN_POINT('',(37.6682,9.525,-33.0365026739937));
#719=LINE('',#718,#717);
#720=CARTESIAN_POINT('',(37.6682,6.985,-33.0365026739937));
#721=VERTEX_POINT('',#720);
#722=CARTESIAN_POINT('',(37.6682,-6.985,-33.0365026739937));
#723=VERTEX_POINT('',#722);
#724=EDGE_CURVE('E314',#721,#723,#719,.T.);
#725=ORIENTED_EDGE('',*,*,#724,.F.);
#726=DIRECTION('',(0.,0.,-1.));
#727=VECTOR('',#726,1.);
#728=CARTESIAN_POINT('',(37.6682,6.985,0.));
#729=LINE('',#728,#727);
#730=EDGE_CURVE('E308',#688,#721,#729,.T.);
#731=ORIENTED_EDGE('',*,*,#730,.F.);
#732=ORIENTED_EDGE('',*,*,#691,.T.);
#733=DIRECTION('',(0.,0.,-1.));
#734=VECTOR('',#733,1.);
#735=CARTESIAN_POINT('',(37.6682,-6.985,0.));
#736=LINE('',#735,#734);
#737=EDGE_CURVE('E279',#690,#723,#736,.T.);
#738=ORIENTED_EDGE('',*,*,#737,.T.);
#739=EDGE_LOOP('',(#725,#731,#732,#738));
#740=FACE_BOUND('',#739,.T.);
#741=ADVANCED_FACE('F307',(#740),#715,.F.);
#742=CARTESIAN_POINT('',(38.8874,9.525,-33.0365026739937));
#743=DIRECTION('',(0.,-1.,0.));
#744=DIRECTION('',(0.,0.,-1.));
#745=AXIS2_PLACEMENT_3D('',#742,#743,#744);
#746=CYLINDRICAL_SURFACE('',#745,1.2192);
#747=ORIENTED_EDGE('',*,*,#420,.T.);
#748=DIRECTION('',(0.,-1.,0.));
#749=VECTOR('',#748,1.);
#750=CARTESIAN_POINT('',(38.0252954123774,9.525,-33.8986072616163));
#751=LINE('',#750,#749);
#752=EDGE_CURVE('E406',#496,#419,#751,.T.);
#753=ORIENTED_EDGE('',*,*,#752,.F.);
#754=ORIENTED_EDGE('',*,*,#497,.F.);
#755=EDGE_CURVE('E309',#485,#721,#719,.T.);
#756=ORIENTED_EDGE('',*,*,#755,.T.);
#757=ORIENTED_EDGE('',*,*,#724,.T.);
#758=DIRECTION('',(0.,1.,0.));
#759=VECTOR('',#758,1.);
#760=CARTESIAN_POINT('',(37.6682,-9.525,-33.0365026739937));
#761=LINE('',#760,#759);
#762=EDGE_CURVE('E415',#417,#723,#761,.T.);
#763=ORIENTED_EDGE('',*,*,#762,.F.);
#764=EDGE_LOOP('',(#747,#753,#754,#756,#757,#763));
#765=FACE_BOUND('',#764,.T.);
#766=ADVANCED_FACE('F414',(#765),#746,.F.);
#767=CARTESIAN_POINT('',(38.0252954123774,9.525,-33.8986072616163));
#768=DIRECTION('',(-0.707106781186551,0.,-0.707106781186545));
#769=DIRECTION('',(-0.707106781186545,0.,0.707106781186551));
#770=AXIS2_PLACEMENT_3D('',#767,#768,#769);
#771=PLANE('',#770);
#772=ORIENTED_EDGE('',*,*,#475,.T.);
#773=DIRECTION('',(0.,-1.,0.));
#774=VECTOR('',#773,1.);
#775=CARTESIAN_POINT('',(38.8514789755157,9.525,-34.7247908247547));
#776=LINE('',#775,#774);
#777=EDGE_CURVE('E404',#504,#468,#776,.T.);
#778=ORIENTED_EDGE('',*,*,#777,.F.);
#779=ORIENTED_EDGE('',*,*,#505,.F.);
#780=ORIENTED_EDGE('',*,*,#752,.T.);
#781=EDGE_LOOP('',(#772,#778,#779,#780));
#782=FACE_BOUND('',#781,.T.);
#783=ADVANCED_FACE('F683',(#782),#771,.F.);
#784=CARTESIAN_POINT('',(37.1272698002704,9.525,-36.449));
#785=DIRECTION('',(0.,-1.,0.));
#786=DIRECTION('',(0.,0.,-1.));
#787=AXIS2_PLACEMENT_3D('',#784,#785,#786);
#788=CYLINDRICAL_SURFACE('',#787,2.4384);
#789=ORIENTED_EDGE('',*,*,#469,.T.);
#790=ORIENTED_EDGE('',*,*,#261,.F.);
#791=ORIENTED_EDGE('',*,*,#512,.F.);
#792=ORIENTED_EDGE('',*,*,#777,.T.);
#793=EDGE_LOOP('',(#789,#790,#791,#792));
#794=FACE_BOUND('',#793,.T.);
#795=ADVANCED_FACE('F681',(#794),#788,.T.);
#796=CARTESIAN_POINT('',(53.5827092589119,0.,-52.3748));
#797=DIRECTION('',(-1.,0.,0.));
#798=DIRECTION('',(0.,0.,1.));
#799=AXIS2_PLACEMENT_3D('',#796,#797,#798);
#800=CYLINDRICAL_SURFACE('',#799,5.9436);
#801=ORIENTED_EDGE('',*,*,#389,.T.);
#802=EDGE_LOOP('',(#801));
#803=FACE_BOUND('',#802,.T.);
#804=ORIENTED_EDGE('',*,*,#355,.F.);
#805=EDGE_LOOP('',(#804));
#806=FACE_BOUND('',#805,.T.);
#807=ADVANCED_FACE('F690',(#803,#806),#800,.F.);
#808=CARTESIAN_POINT('',(19.7702635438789,-5.9436,-51.1809999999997));
#809=DIRECTION('',(0.,-1.,0.));
#810=DIRECTION('',(0.,0.,-1.));
#811=AXIS2_PLACEMENT_3D('',#808,#809,#810);
#812=PLANE('',#811);
#813=DIRECTION('',(1.,0.,0.));
#814=VECTOR('',#813,1.);
#815=CARTESIAN_POINT('',(19.7702635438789,-5.9436,-51.1809999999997));
#816=LINE('',#815,#814);
#817=EDGE_CURVE('E576',#276,#210,#816,.T.);
#818=ORIENTED_EDGE('',*,*,#817,.T.);
#819=ORIENTED_EDGE('',*,*,#211,.T.);
#820=DIRECTION('',(1.,0.,0.));
#821=VECTOR('',#820,1.);
#822=CARTESIAN_POINT('',(19.7702635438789,-5.9436,-53.5686000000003));
#823=LINE('',#822,#821);
#824=EDGE_CURVE('E572',#278,#200,#823,.T.);
#825=ORIENTED_EDGE('',*,*,#824,.F.);
#826=ORIENTED_EDGE('',*,*,#279,.F.);
#827=EDGE_LOOP('',(#818,#819,#825,#826));
#828=FACE_BOUND('',#827,.T.);
#829=ADVANCED_FACE('F733',(#828),#812,.F.);
#830=CARTESIAN_POINT('',(19.7702635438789,0.,-53.5685999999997));
#831=DIRECTION('',(1.,0.,0.));
#832=DIRECTION('',(0.,0.,-1.));
#833=AXIS2_PLACEMENT_3D('',#830,#831,#832);
#834=CYLINDRICAL_SURFACE('',#833,5.9436);
#835=ORIENTED_EDGE('',*,*,#824,.T.);
#836=ORIENTED_EDGE('',*,*,#203,.T.);
#837=DIRECTION('',(1.,0.,0.));
#838=VECTOR('',#837,1.);
#839=CARTESIAN_POINT('',(19.7702635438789,5.9436,-53.5686000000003));
#840=LINE('',#839,#838);
#841=EDGE_CURVE('E581',#287,#202,#840,.T.);
#842=ORIENTED_EDGE('',*,*,#841,.F.);
#843=ORIENTED_EDGE('',*,*,#288,.F.);
#844=EDGE_LOOP('',(#835,#836,#842,#843));
#845=FACE_BOUND('',#844,.T.);
#846=ADVANCED_FACE('F737',(#845),#834,.F.);
#847=CARTESIAN_POINT('',(19.7702635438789,5.9436,-51.1809999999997));
#848=DIRECTION('',(0.,1.,0.));
#849=DIRECTION('',(0.,0.,1.));
#850=AXIS2_PLACEMENT_3D('',#847,#848,#849);
#851=PLANE('',#850);
#852=ORIENTED_EDGE('',*,*,#841,.T.);
#853=ORIENTED_EDGE('',*,*,#226,.T.);
#854=DIRECTION('',(1.,0.,0.));
#855=VECTOR('',#854,1.);
#856=CARTESIAN_POINT('',(19.7702635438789,5.9436,-51.1809999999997));
#857=LINE('',#856,#855);
#858=EDGE_CURVE('E577',#295,#219,#857,.T.);
#859=ORIENTED_EDGE('',*,*,#858,.F.);
#860=ORIENTED_EDGE('',*,*,#296,.F.);
#861=EDGE_LOOP('',(#852,#853,#859,#860));
#862=FACE_BOUND('',#861,.T.);
#863=ADVANCED_FACE('F741',(#862),#851,.F.);
#864=CARTESIAN_POINT('',(19.7702635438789,0.,-51.1809999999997));
#865=DIRECTION('',(1.,0.,0.));
#866=DIRECTION('',(0.,0.,-1.));
#867=AXIS2_PLACEMENT_3D('',#864,#865,#866);
#868=CYLINDRICAL_SURFACE('',#867,5.9436);
#869=ORIENTED_EDGE('',*,*,#858,.T.);
#870=ORIENTED_EDGE('',*,*,#220,.T.);
#871=ORIENTED_EDGE('',*,*,#817,.F.);
#872=ORIENTED_EDGE('',*,*,#303,.F.);
#873=EDGE_LOOP('',(#869,#870,#871,#872));
#874=FACE_BOUND('',#873,.T.);
#875=ADVANCED_FACE('F745',(#874),#868,.F.);
#876=CARTESIAN_POINT('',(39.5656698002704,0.,-42.8498));
#877=DIRECTION('',(-1.,0.,0.));
#878=DIRECTION('',(0.,0.,1.));
#879=AXIS2_PLACEMENT_3D('',#876,#877,#878);
#880=CYLINDRICAL_SURFACE('',#879,22.225);
#881=ORIENTED_EDGE('',*,*,#365,.F.);
#882=ORIENTED_EDGE('',*,*,#65,.T.);
#883=ORIENTED_EDGE('',*,*,#398,.F.);
#884=ORIENTED_EDGE('',*,*,#147,.F.);
#885=EDGE_LOOP('',(#881,#882,#883,#884));
#886=FACE_BOUND('',#885,.T.);
#887=ADVANCED_FACE('F624',(#886),#880,.T.);
#888=ORIENTED_EDGE('',*,*,#519,.F.);
#889=ORIENTED_EDGE('',*,*,#247,.T.);
#890=ORIENTED_EDGE('',*,*,#459,.T.);
#891=ORIENTED_EDGE('',*,*,#316,.F.);
#892=EDGE_LOOP('',(#888,#889,#890,#891));
#893=FACE_BOUND('',#892,.T.);
#894=ADVANCED_FACE('F672',(#893),#880,.T.);
#895=CARTESIAN_POINT('',(5.49755169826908E-13,11.049,-39.1922));
#896=DIRECTION('',(0.,0.,1.));
#897=DIRECTION('',(1.,0.,0.));
#898=AXIS2_PLACEMENT_3D('',#895,#896,#897);
#899=PLANE('',#898);
#900=DIRECTION('',(0.,-1.,0.));
#901=VECTOR('',#900,1.);
#902=CARTESIAN_POINT('',(5.49755169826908E-13,11.049,-39.1922));
#903=LINE('',#902,#901);
#904=CARTESIAN_POINT('',(5.49755169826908E-13,11.049,-39.1922));
#905=VERTEX_POINT('',#904);
#906=CARTESIAN_POINT('',(5.49755169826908E-13,6.985,-39.1922));
#907=VERTEX_POINT('',#906);
#908=EDGE_CURVE('E304',#905,#907,#903,.T.);
#909=ORIENTED_EDGE('',*,*,#908,.F.);
#910=DIRECTION('',(1.,0.,0.));
#911=VECTOR('',#910,1.);
#912=CARTESIAN_POINT('',(5.49755169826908E-13,11.049,-39.1922));
#913=LINE('',#912,#911);
#914=CARTESIAN_POINT('',(34.282469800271,11.049,-39.1922));
#915=VERTEX_POINT('',#914);
#916=EDGE_CURVE('E539',#905,#915,#913,.T.);
#917=ORIENTED_EDGE('',*,*,#916,.T.);
#918=DIRECTION('',(0.,-1.,0.));
#919=VECTOR('',#918,1.);
#920=CARTESIAN_POINT('',(34.282469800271,11.049,-39.1922));
#921=LINE('',#920,#919);
#922=CARTESIAN_POINT('',(34.282469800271,6.985,-39.1922));
#923=VERTEX_POINT('',#922);
#924=EDGE_CURVE('E521',#915,#923,#921,.T.);
#925=ORIENTED_EDGE('',*,*,#924,.T.);
#926=DIRECTION('',(1.,0.,0.));
#927=VECTOR('',#926,1.);
#928=CARTESIAN_POINT('',(5.49755169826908E-13,6.985,-39.1922));
#929=LINE('',#928,#927);
#930=EDGE_CURVE('E542',#907,#923,#929,.T.);
#931=ORIENTED_EDGE('',*,*,#930,.F.);
#932=EDGE_LOOP('',(#909,#917,#925,#931));
#933=FACE_BOUND('',#932,.T.);
#934=ADVANCED_FACE('F836',(#933),#899,.F.);
#935=CARTESIAN_POINT('',(4.89898482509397E-13,11.049,-34.925));
#936=DIRECTION('',(0.,0.,-1.));
#937=DIRECTION('',(-1.,0.,0.));
#938=AXIS2_PLACEMENT_3D('',#935,#936,#937);
#939=PLANE('',#938);
#940=DIRECTION('',(0.,1.,0.));
#941=VECTOR('',#940,1.);
#942=CARTESIAN_POINT('',(4.89898482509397E-13,11.049,-34.925));
#943=LINE('',#942,#941);
#944=CARTESIAN_POINT('',(4.89898482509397E-13,-11.049,-34.925));
#945=VERTEX_POINT('',#944);
#946=CARTESIAN_POINT('',(4.89898482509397E-13,11.049,-34.925));
#947=VERTEX_POINT('',#946);
#948=EDGE_CURVE('E472',#945,#947,#943,.T.);
#949=ORIENTED_EDGE('',*,*,#948,.F.);
#950=DIRECTION('',(1.,0.,0.));
#951=VECTOR('',#950,1.);
#952=CARTESIAN_POINT('',(4.89898482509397E-13,-11.049,-34.925));
#953=LINE('',#952,#951);
#954=CARTESIAN_POINT('',(34.2824698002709,-11.049,-34.925));
#955=VERTEX_POINT('',#954);
#956=EDGE_CURVE('E533',#945,#955,#953,.T.);
#957=ORIENTED_EDGE('',*,*,#956,.T.);
#958=DIRECTION('',(0.,1.,0.));
#959=VECTOR('',#958,1.);
#960=CARTESIAN_POINT('',(34.2824698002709,11.049,-34.925));
#961=LINE('',#960,#959);
#962=CARTESIAN_POINT('',(34.2824698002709,11.049,-34.925));
#963=VERTEX_POINT('',#962);
#964=EDGE_CURVE('E517',#955,#963,#961,.T.);
#965=ORIENTED_EDGE('',*,*,#964,.T.);
#966=DIRECTION('',(1.,0.,0.));
#967=VECTOR('',#966,1.);
#968=CARTESIAN_POINT('',(4.89898482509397E-13,11.049,-34.925));
#969=LINE('',#968,#967);
#970=EDGE_CURVE('E536',#947,#963,#969,.T.);
#971=ORIENTED_EDGE('',*,*,#970,.F.);
#972=EDGE_LOOP('',(#949,#957,#965,#971));
#973=FACE_BOUND('',#972,.T.);
#974=ADVANCED_FACE('F922',(#973),#939,.F.);
#975=CARTESIAN_POINT('',(5.49755169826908E-13,-11.049,-39.1922));
#976=DIRECTION('',(0.,0.,1.));
#977=DIRECTION('',(1.,0.,0.));
#978=AXIS2_PLACEMENT_3D('',#975,#976,#977);
#979=PLANE('',#978);
#980=DIRECTION('',(0.,-1.,0.));
#981=VECTOR('',#980,1.);
#982=CARTESIAN_POINT('',(5.49755169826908E-13,-11.049,-39.1922));
#983=LINE('',#982,#981);
#984=CARTESIAN_POINT('',(5.49755169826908E-13,-6.985,-39.1922));
#985=VERTEX_POINT('',#984);
#986=CARTESIAN_POINT('',(5.49755169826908E-13,-11.049,-39.1922));
#987=VERTEX_POINT('',#986);
#988=EDGE_CURVE('E458',#985,#987,#983,.T.);
#989=ORIENTED_EDGE('',*,*,#988,.F.);
#990=DIRECTION('',(1.,0.,0.));
#991=VECTOR('',#990,1.);
#992=CARTESIAN_POINT('',(5.49755169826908E-13,-6.985,-39.1922));
#993=LINE('',#992,#991);
#994=CARTESIAN_POINT('',(34.282469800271,-6.985,-39.1922));
#995=VERTEX_POINT('',#994);
#996=EDGE_CURVE('E527',#985,#995,#993,.T.);
#997=ORIENTED_EDGE('',*,*,#996,.T.);
#998=DIRECTION('',(0.,-1.,0.));
#999=VECTOR('',#998,1.);
#1000=CARTESIAN_POINT('',(34.282469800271,-11.049,-39.1922));
#1001=LINE('',#1000,#999);
#1002=CARTESIAN_POINT('',(34.282469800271,-11.049,-39.1922));
#1003=VERTEX_POINT('',#1002);
#1004=EDGE_CURVE('E513',#995,#1003,#1001,.T.);
#1005=ORIENTED_EDGE('',*,*,#1004,.T.);
#1006=DIRECTION('',(1.,0.,0.));
#1007=VECTOR('',#1006,1.);
#1008=CARTESIAN_POINT('',(5.49755169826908E-13,-11.049,-39.1922));
#1009=LINE('',#1008,#1007);
#1010=EDGE_CURVE('E530',#987,#1003,#1009,.T.);
#1011=ORIENTED_EDGE('',*,*,#1010,.F.);
#1012=EDGE_LOOP('',(#989,#997,#1005,#1011));
#1013=FACE_BOUND('',#1012,.T.);
#1014=ADVANCED_FACE('F643',(#1013),#979,.F.);
#1015=CARTESIAN_POINT('',(0.,9.525,0.));
#1016=DIRECTION('',(0.,-1.,0.));
#1017=DIRECTION('',(0.,0.,-1.));
#1018=AXIS2_PLACEMENT_3D('',#1015,#1016,#1017);
#1019=CYLINDRICAL_SURFACE('',#1018,39.1922);
#1020=DIRECTION('',(0.,-1.,0.));
#1021=VECTOR('',#1020,1.);
#1022=CARTESIAN_POINT('',(39.1922,11.049,0.));
#1023=LINE('',#1022,#1021);
#1024=CARTESIAN_POINT('',(39.1922,11.049,0.));
#1025=VERTEX_POINT('',#1024);
#1026=CARTESIAN_POINT('',(39.1922,6.985,0.));
#1027=VERTEX_POINT('',#1026);
#1028=EDGE_CURVE('E293',#1025,#1027,#1023,.T.);
#1029=ORIENTED_EDGE('',*,*,#1028,.F.);
#1030=CARTESIAN_POINT('',(0.,11.049,0.));
#1031=DIRECTION('',(0.,-1.,0.));
#1032=DIRECTION('',(0.,0.,-1.));
#1033=AXIS2_PLACEMENT_3D('',#1030,#1031,#1032);
#1034=CIRCLE('',#1033,39.1922);
#1035=EDGE_CURVE('E488',#1025,#905,#1034,.T.);
#1036=ORIENTED_EDGE('',*,*,#1035,.T.);
#1037=ORIENTED_EDGE('',*,*,#908,.T.);
#1038=CARTESIAN_POINT('',(0.,6.985,0.));
#1039=DIRECTION('',(0.,-1.,0.));
#1040=DIRECTION('',(0.,0.,-1.));
#1041=AXIS2_PLACEMENT_3D('',#1038,#1039,#1040);
#1042=CIRCLE('',#1041,39.1922);
#1043=EDGE_CURVE('E491',#1027,#907,#1042,.T.);
#1044=ORIENTED_EDGE('',*,*,#1043,.F.);
#1045=EDGE_LOOP('',(#1029,#1036,#1037,#1044));
#1046=FACE_BOUND('',#1045,.T.);
#1047=ADVANCED_FACE('F942',(#1046),#1019,.T.);
#1048=CARTESIAN_POINT('',(0.,9.525,0.));
#1049=DIRECTION('',(0.,-1.,0.));
#1050=DIRECTION('',(0.,0.,-1.));
#1051=AXIS2_PLACEMENT_3D('',#1048,#1049,#1050);
#1052=CYLINDRICAL_SURFACE('',#1051,34.925);
#1053=DIRECTION('',(0.,1.,0.));
#1054=VECTOR('',#1053,1.);
#1055=CARTESIAN_POINT('',(34.925,11.049,0.));
#1056=LINE('',#1055,#1054);
#1057=CARTESIAN_POINT('',(34.925,-11.049,0.));
#1058=VERTEX_POINT('',#1057);
#1059=CARTESIAN_POINT('',(34.925,11.049,0.));
#1060=VERTEX_POINT('',#1059);
#1061=EDGE_CURVE('E1105',#1058,#1060,#1056,.T.);
#1062=ORIENTED_EDGE('',*,*,#1061,.F.);
#1063=CARTESIAN_POINT('',(0.,-11.049,0.));
#1064=DIRECTION('',(0.,-1.,0.));
#1065=DIRECTION('',(0.,0.,-1.));
#1066=AXIS2_PLACEMENT_3D('',#1063,#1064,#1065);
#1067=CIRCLE('',#1066,34.925);
#1068=EDGE_CURVE('E482',#1058,#945,#1067,.T.);
#1069=ORIENTED_EDGE('',*,*,#1068,.T.);
#1070=ORIENTED_EDGE('',*,*,#948,.T.);
#1071=CARTESIAN_POINT('',(0.,11.049,0.));
#1072=DIRECTION('',(0.,-1.,0.));
#1073=DIRECTION('',(0.,0.,-1.));
#1074=AXIS2_PLACEMENT_3D('',#1071,#1072,#1073);
#1075=CIRCLE('',#1074,34.925);
#1076=EDGE_CURVE('E485',#1060,#947,#1075,.T.);
#1077=ORIENTED_EDGE('',*,*,#1076,.F.);
#1078=EDGE_LOOP('',(#1062,#1069,#1070,#1077));
#1079=FACE_BOUND('',#1078,.T.);
#1080=ADVANCED_FACE('F952',(#1079),#1052,.F.);
#1081=CARTESIAN_POINT('',(0.,9.525,0.));
#1082=DIRECTION('',(0.,-1.,0.));
#1083=DIRECTION('',(0.,0.,-1.));
#1084=AXIS2_PLACEMENT_3D('',#1081,#1082,#1083);
#1085=CYLINDRICAL_SURFACE('',#1084,39.1922);
#1086=DIRECTION('',(0.,-1.,0.));
#1087=VECTOR('',#1086,1.);
#1088=CARTESIAN_POINT('',(39.1922,-11.049,0.));
#1089=LINE('',#1088,#1087);
#1090=CARTESIAN_POINT('',(39.1922,-6.985,0.));
#1091=VERTEX_POINT('',#1090);
#1092=CARTESIAN_POINT('',(39.1922,-11.049,0.));
#1093=VERTEX_POINT('',#1092);
#1094=EDGE_CURVE('E456',#1091,#1093,#1089,.T.);
#1095=ORIENTED_EDGE('',*,*,#1094,.F.);
#1096=CARTESIAN_POINT('',(0.,-6.985,0.));
#1097=DIRECTION('',(0.,-1.,0.));
#1098=DIRECTION('',(0.,0.,-1.));
#1099=AXIS2_PLACEMENT_3D('',#1096,#1097,#1098);
#1100=CIRCLE('',#1099,39.1922);
#1101=EDGE_CURVE('E303',#1091,#985,#1100,.T.);
#1102=ORIENTED_EDGE('',*,*,#1101,.T.);
#1103=ORIENTED_EDGE('',*,*,#988,.T.);
#1104=CARTESIAN_POINT('',(0.,-11.049,0.));
#1105=DIRECTION('',(0.,-1.,0.));
#1106=DIRECTION('',(0.,0.,-1.));
#1107=AXIS2_PLACEMENT_3D('',#1104,#1105,#1106);
#1108=CIRCLE('',#1107,39.1922);
#1109=EDGE_CURVE('E479',#1093,#987,#1108,.T.);
#1110=ORIENTED_EDGE('',*,*,#1109,.F.);
#1111=EDGE_LOOP('',(#1095,#1102,#1103,#1110));
#1112=FACE_BOUND('',#1111,.T.);
#1113=ADVANCED_FACE('F646',(#1112),#1085,.T.);
#1114=CARTESIAN_POINT('',(39.1922,6.985,0.));
#1115=DIRECTION('',(0.,-1.,0.));
#1116=DIRECTION('',(0.,0.,-1.));
#1117=AXIS2_PLACEMENT_3D('',#1114,#1115,#1116);
#1118=PLANE('',#1117);
#1119=DIRECTION('',(-1.,0.,0.));
#1120=VECTOR('',#1119,1.);
#1121=CARTESIAN_POINT('',(39.1922,6.985,-33.0365026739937));
#1122=LINE('',#1121,#1120);
#1123=CARTESIAN_POINT('',(39.1922,6.985,-33.0365026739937));
#1124=VERTEX_POINT('',#1123);
#1125=EDGE_CURVE('E426',#1124,#721,#1122,.T.);
#1126=ORIENTED_EDGE('',*,*,#1125,.F.);
#1127=DIRECTION('',(0.,0.,-1.));
#1128=VECTOR('',#1127,1.);
#1129=CARTESIAN_POINT('',(39.1922,6.985,0.));
#1130=LINE('',#1129,#1128);
#1131=EDGE_CURVE('E459',#1027,#1124,#1130,.T.);
#1132=ORIENTED_EDGE('',*,*,#1131,.F.);
#1133=ORIENTED_EDGE('',*,*,#1043,.T.);
#1134=ORIENTED_EDGE('',*,*,#930,.T.);
#1135=DIRECTION('',(0.,0.,1.));
#1136=VECTOR('',#1135,1.);
#1137=CARTESIAN_POINT('',(34.282469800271,6.985,-39.1922));
#1138=LINE('',#1137,#1136);
#1139=EDGE_CURVE('E523',#923,#649,#1138,.T.);
#1140=ORIENTED_EDGE('',*,*,#1139,.T.);
#1141=ORIENTED_EDGE('',*,*,#650,.F.);
#1142=ORIENTED_EDGE('',*,*,#698,.F.);
#1143=ORIENTED_EDGE('',*,*,#730,.T.);
#1144=EDGE_LOOP('',(#1126,#1132,#1133,#1134,#1140,#1141,#1142,#1143));
#1145=FACE_BOUND('',#1144,.T.);
#1146=ADVANCED_FACE('F973',(#1145),#1118,.T.);
#1147=CARTESIAN_POINT('',(39.1922,11.049,0.));
#1148=DIRECTION('',(1.,0.,0.));
#1149=DIRECTION('',(0.,0.,-1.));
#1150=AXIS2_PLACEMENT_3D('',#1147,#1148,#1149);
#1151=PLANE('',#1150);
#1152=DIRECTION('',(0.,-1.,0.));
#1153=VECTOR('',#1152,1.);
#1154=CARTESIAN_POINT('',(39.1922,11.049,-33.0365026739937));
#1155=LINE('',#1154,#1153);
#1156=CARTESIAN_POINT('',(39.1922,11.049,-33.0365026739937));
#1157=VERTEX_POINT('',#1156);
#1158=EDGE_CURVE('E453',#1157,#1124,#1155,.T.);
#1159=ORIENTED_EDGE('',*,*,#1158,.F.);
#1160=DIRECTION('',(0.,0.,-1.));
#1161=VECTOR('',#1160,1.);
#1162=CARTESIAN_POINT('',(39.1922,11.049,0.));
#1163=LINE('',#1162,#1161);
#1164=EDGE_CURVE('E461',#1025,#1157,#1163,.T.);
#1165=ORIENTED_EDGE('',*,*,#1164,.F.);
#1166=ORIENTED_EDGE('',*,*,#1028,.T.);
#1167=ORIENTED_EDGE('',*,*,#1131,.T.);
#1168=EDGE_LOOP('',(#1159,#1165,#1166,#1167));
#1169=FACE_BOUND('',#1168,.T.);
#1170=ADVANCED_FACE('F984',(#1169),#1151,.T.);
#1171=CARTESIAN_POINT('',(39.1922,11.049,0.));
#1172=DIRECTION('',(0.,1.,0.));
#1173=DIRECTION('',(0.,0.,1.));
#1174=AXIS2_PLACEMENT_3D('',#1171,#1172,#1173);
#1175=PLANE('',#1174);
#1176=DIRECTION('',(1.,0.,0.));
#1177=VECTOR('',#1176,1.);
#1178=CARTESIAN_POINT('',(39.1922,11.049,-33.0365026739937));
#1179=LINE('',#1178,#1177);
#1180=CARTESIAN_POINT('',(34.925,11.049,-33.0365026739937));
#1181=VERTEX_POINT('',#1180);
#1182=EDGE_CURVE('E450',#1181,#1157,#1179,.T.);
#1183=ORIENTED_EDGE('',*,*,#1182,.F.);
#1184=DIRECTION('',(0.,0.,-1.));
#1185=VECTOR('',#1184,1.);
#1186=CARTESIAN_POINT('',(34.925,11.049,0.));
#1187=LINE('',#1186,#1185);
#1188=EDGE_CURVE('E463',#1060,#1181,#1187,.T.);
#1189=ORIENTED_EDGE('',*,*,#1188,.F.);
#1190=ORIENTED_EDGE('',*,*,#1076,.T.);
#1191=ORIENTED_EDGE('',*,*,#970,.T.);
#1192=DIRECTION('',(0.,0.,-1.));
#1193=VECTOR('',#1192,1.);
#1194=CARTESIAN_POINT('',(34.282469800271,11.049,-39.1922));
#1195=LINE('',#1194,#1193);
#1196=EDGE_CURVE('E519',#963,#915,#1195,.T.);
#1197=ORIENTED_EDGE('',*,*,#1196,.T.);
#1198=ORIENTED_EDGE('',*,*,#916,.F.);
#1199=ORIENTED_EDGE('',*,*,#1035,.F.);
#1200=ORIENTED_EDGE('',*,*,#1164,.T.);
#1201=EDGE_LOOP('',(#1183,#1189,#1190,#1191,#1197,#1198,#1199,#1200));
#1202=FACE_BOUND('',#1201,.T.);
#1203=ADVANCED_FACE('F996',(#1202),#1175,.T.);
#1204=CARTESIAN_POINT('',(34.925,11.049,0.));
#1205=DIRECTION('',(-1.,0.,0.));
#1206=DIRECTION('',(0.,0.,1.));
#1207=AXIS2_PLACEMENT_3D('',#1204,#1205,#1206);
#1208=PLANE('',#1207);
#1209=DIRECTION('',(0.,1.,0.));
#1210=VECTOR('',#1209,1.);
#1211=CARTESIAN_POINT('',(34.925,11.049,-33.0365026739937));
#1212=LINE('',#1211,#1210);
#1213=CARTESIAN_POINT('',(34.925,-11.049,-33.0365026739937));
#1214=VERTEX_POINT('',#1213);
#1215=EDGE_CURVE('E447',#1214,#1181,#1212,.T.);
#1216=ORIENTED_EDGE('',*,*,#1215,.F.);
#1217=DIRECTION('',(0.,0.,-1.));
#1218=VECTOR('',#1217,1.);
#1219=CARTESIAN_POINT('',(34.925,-11.049,0.));
#1220=LINE('',#1219,#1218);
#1221=EDGE_CURVE('E465',#1058,#1214,#1220,.T.);
#1222=ORIENTED_EDGE('',*,*,#1221,.F.);
#1223=ORIENTED_EDGE('',*,*,#1061,.T.);
#1224=ORIENTED_EDGE('',*,*,#1188,.T.);
#1225=EDGE_LOOP('',(#1216,#1222,#1223,#1224));
#1226=FACE_BOUND('',#1225,.T.);
#1227=ADVANCED_FACE('F1008',(#1226),#1208,.T.);
#1228=CARTESIAN_POINT('',(34.925,-11.049,0.));
#1229=DIRECTION('',(0.,-1.,0.));
#1230=DIRECTION('',(0.,0.,-1.));
#1231=AXIS2_PLACEMENT_3D('',#1228,#1229,#1230);
#1232=PLANE('',#1231);
#1233=DIRECTION('',(-1.,0.,0.));
#1234=VECTOR('',#1233,1.);
#1235=CARTESIAN_POINT('',(34.925,-11.049,-33.0365026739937));
#1236=LINE('',#1235,#1234);
#1237=CARTESIAN_POINT('',(39.1922,-11.049,-33.0365026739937));
#1238=VERTEX_POINT('',#1237);
#1239=EDGE_CURVE('E444',#1238,#1214,#1236,.T.);
#1240=ORIENTED_EDGE('',*,*,#1239,.F.);
#1241=DIRECTION('',(0.,0.,-1.));
#1242=VECTOR('',#1241,1.);
#1243=CARTESIAN_POINT('',(39.1922,-11.049,0.));
#1244=LINE('',#1243,#1242);
#1245=EDGE_CURVE('E467',#1093,#1238,#1244,.T.);
#1246=ORIENTED_EDGE('',*,*,#1245,.F.);
#1247=ORIENTED_EDGE('',*,*,#1109,.T.);
#1248=ORIENTED_EDGE('',*,*,#1010,.T.);
#1249=DIRECTION('',(0.,0.,1.));
#1250=VECTOR('',#1249,1.);
#1251=CARTESIAN_POINT('',(34.2824698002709,-11.049,-34.925));
#1252=LINE('',#1251,#1250);
#1253=EDGE_CURVE('E515',#1003,#955,#1252,.T.);
#1254=ORIENTED_EDGE('',*,*,#1253,.T.);
#1255=ORIENTED_EDGE('',*,*,#956,.F.);
#1256=ORIENTED_EDGE('',*,*,#1068,.F.);
#1257=ORIENTED_EDGE('',*,*,#1221,.T.);
#1258=EDGE_LOOP('',(#1240,#1246,#1247,#1248,#1254,#1255,#1256,#1257));
#1259=FACE_BOUND('',#1258,.T.);
#1260=ADVANCED_FACE('F1020',(#1259),#1232,.T.);
#1261=CARTESIAN_POINT('',(39.1922,-11.049,0.));
#1262=DIRECTION('',(1.,0.,0.));
#1263=DIRECTION('',(0.,0.,-1.));
#1264=AXIS2_PLACEMENT_3D('',#1261,#1262,#1263);
#1265=PLANE('',#1264);
#1266=DIRECTION('',(0.,-1.,0.));
#1267=VECTOR('',#1266,1.);
#1268=CARTESIAN_POINT('',(39.1922,-11.049,-33.0365026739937));
#1269=LINE('',#1268,#1267);
#1270=CARTESIAN_POINT('',(39.1922,-6.985,-33.0365026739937));
#1271=VERTEX_POINT('',#1270);
#1272=EDGE_CURVE('E441',#1271,#1238,#1269,.T.);
#1273=ORIENTED_EDGE('',*,*,#1272,.F.);
#1274=DIRECTION('',(0.,0.,-1.));
#1275=VECTOR('',#1274,1.);
#1276=CARTESIAN_POINT('',(39.1922,-6.985,0.));
#1277=LINE('',#1276,#1275);
#1278=EDGE_CURVE('E292',#1091,#1271,#1277,.T.);
#1279=ORIENTED_EDGE('',*,*,#1278,.F.);
#1280=ORIENTED_EDGE('',*,*,#1094,.T.);
#1281=ORIENTED_EDGE('',*,*,#1245,.T.);
#1282=EDGE_LOOP('',(#1273,#1279,#1280,#1281));
#1283=FACE_BOUND('',#1282,.T.);
#1284=ADVANCED_FACE('F651',(#1283),#1265,.T.);
#1285=CARTESIAN_POINT('',(37.6682,-6.985,0.));
#1286=DIRECTION('',(0.,1.,0.));
#1287=DIRECTION('',(0.,0.,1.));
#1288=AXIS2_PLACEMENT_3D('',#1285,#1286,#1287);
#1289=PLANE('',#1288);
#1290=DIRECTION('',(1.,0.,0.));
#1291=VECTOR('',#1290,1.);
#1292=CARTESIAN_POINT('',(37.6682,-6.985,-33.0365026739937));
#1293=LINE('',#1292,#1291);
#1294=EDGE_CURVE('E286',#723,#1271,#1293,.T.);
#1295=ORIENTED_EDGE('',*,*,#1294,.F.);
#1296=ORIENTED_EDGE('',*,*,#737,.F.);
#1297=ORIENTED_EDGE('',*,*,#706,.T.);
#1298=ORIENTED_EDGE('',*,*,#673,.T.);
#1299=DIRECTION('',(0.,0.,-1.));
#1300=VECTOR('',#1299,1.);
#1301=CARTESIAN_POINT('',(34.282469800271,-6.985,-37.6682));
#1302=LINE('',#1301,#1300);
#1303=EDGE_CURVE('E511',#666,#995,#1302,.T.);
#1304=ORIENTED_EDGE('',*,*,#1303,.T.);
#1305=ORIENTED_EDGE('',*,*,#996,.F.);
#1306=ORIENTED_EDGE('',*,*,#1101,.F.);
#1307=ORIENTED_EDGE('',*,*,#1278,.T.);
#1308=EDGE_LOOP('',(#1295,#1296,#1297,#1298,#1304,#1305,#1306,#1307));
#1309=FACE_BOUND('',#1308,.T.);
#1310=ADVANCED_FACE('F281',(#1309),#1289,.T.);
#1311=CARTESIAN_POINT('',(34.2824698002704,0.,0.));
#1312=DIRECTION('',(-1.,0.,0.));
#1313=DIRECTION('',(0.,0.,1.));
#1314=AXIS2_PLACEMENT_3D('',#1311,#1312,#1313);
#1315=PLANE('',#1314);
#1316=ORIENTED_EDGE('',*,*,#656,.F.);
#1317=ORIENTED_EDGE('',*,*,#1139,.F.);
#1318=ORIENTED_EDGE('',*,*,#924,.F.);
#1319=ORIENTED_EDGE('',*,*,#1196,.F.);
#1320=ORIENTED_EDGE('',*,*,#964,.F.);
#1321=ORIENTED_EDGE('',*,*,#1253,.F.);
#1322=ORIENTED_EDGE('',*,*,#1004,.F.);
#1323=ORIENTED_EDGE('',*,*,#1303,.F.);
#1324=ORIENTED_EDGE('',*,*,#667,.F.);
#1325=ORIENTED_EDGE('',*,*,#32,.F.);
#1326=ORIENTED_EDGE('',*,*,#177,.F.);
#1327=ORIENTED_EDGE('',*,*,#114,.F.);
#1328=EDGE_LOOP('',(#1316,#1317,#1318,#1319,#1320,#1321,#1322,#1323,#1324,#1325,#1326,#1327));
#1329=FACE_BOUND('',#1328,.T.);
#1330=ADVANCED_FACE('F636',(#1329),#1315,.F.);
#1331=CARTESIAN_POINT('',(0.,0.,-33.0365026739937));
#1332=DIRECTION('',(0.,0.,-1.));
#1333=DIRECTION('',(-1.,0.,0.));
#1334=AXIS2_PLACEMENT_3D('',#1331,#1332,#1333);
#1335=PLANE('',#1334);
#1336=ORIENTED_EDGE('',*,*,#755,.F.);
#1337=ORIENTED_EDGE('',*,*,#488,.T.);
#1338=ORIENTED_EDGE('',*,*,#593,.T.);
#1339=ORIENTED_EDGE('',*,*,#428,.T.);
#1340=ORIENTED_EDGE('',*,*,#762,.T.);
#1341=ORIENTED_EDGE('',*,*,#1294,.T.);
#1342=ORIENTED_EDGE('',*,*,#1272,.T.);
#1343=ORIENTED_EDGE('',*,*,#1239,.T.);
#1344=ORIENTED_EDGE('',*,*,#1215,.T.);
#1345=ORIENTED_EDGE('',*,*,#1182,.T.);
#1346=ORIENTED_EDGE('',*,*,#1158,.T.);
#1347=ORIENTED_EDGE('',*,*,#1125,.T.);
#1348=EDGE_LOOP('',(#1336,#1337,#1338,#1339,#1340,#1341,#1342,#1343,#1344,#1345,#1346,#1347));
#1349=FACE_BOUND('',#1348,.T.);
#1350=ADVANCED_FACE('F421',(#1349),#1335,.T.);
#1351=CLOSED_SHELL('',(#92,#166,#188,#265,#342,#376,#410,#479,#548,#565,#582,#599,#611,#628,
#677,#710,#741,#766,#783,#795,#807,#829,#846,#863,#875,#887,#894,#934,#974,#1014,#1047,#1080,
#1113,#1146,#1170,#1203,#1227,#1260,#1284,#1310,#1330,#1350));
#1352=MANIFOLD_SOLID_BREP('B2',#1351);
#1353=ADVANCED_BREP_SHAPE_REPRESENTATION('',(#18,#1352),#14);
#1354=SHAPE_DEFINITION_REPRESENTATION(#9,#1353);
ENDSEC;
END-ISO-10303-21;
